VERSION 5.7 ;
  NOWIREEXTENSIONATPIN ON ;
  DIVIDERCHAR "/" ;
  BUSBITCHARS "[]" ;
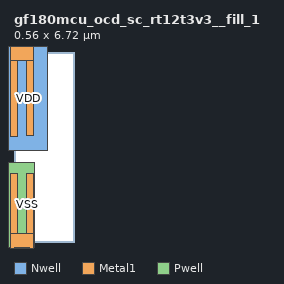
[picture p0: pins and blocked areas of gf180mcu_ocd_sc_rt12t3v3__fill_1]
MACRO gf180mcu_ocd_sc_rt12t3v3__fill_1
  CLASS CORE SPACER ;
  FOREIGN gf180mcu_ocd_sc_rt12t3v3__fill_1 ;
  ORIGIN 0.000 0.000 ;
  SIZE 0.560 BY 6.720 ;
  SYMMETRY X Y ;
  SITE unithd ;
  PIN VDD
    DIRECTION INOUT ;
    USE POWER ;
    SHAPE ABUTMENT ;
    PORT
      LAYER Nwell ;
        RECT -0.610 3.245 1.170 7.330 ;
      LAYER Metal1 ;
        RECT -0.115 6.420 0.675 7.020 ;
        RECT -0.115 3.745 0.115 6.420 ;
        RECT 0.445 3.750 0.675 6.420 ;
    END
  END VDD
  PIN VSS
    DIRECTION INOUT ;
    USE GROUND ;
    SHAPE ABUTMENT ;
    PORT
      LAYER Pwell ;
        RECT -0.180 -0.180 0.740 2.815 ;
        RECT 0.000 -0.300 0.560 -0.180 ;
      LAYER Metal1 ;
        RECT -0.115 0.300 0.115 2.410 ;
        RECT 0.445 0.300 0.675 2.410 ;
        RECT -0.115 -0.300 0.675 0.300 ;
    END
  END VSS
END gf180mcu_ocd_sc_rt12t3v3__fill_1
END LIBRARY

